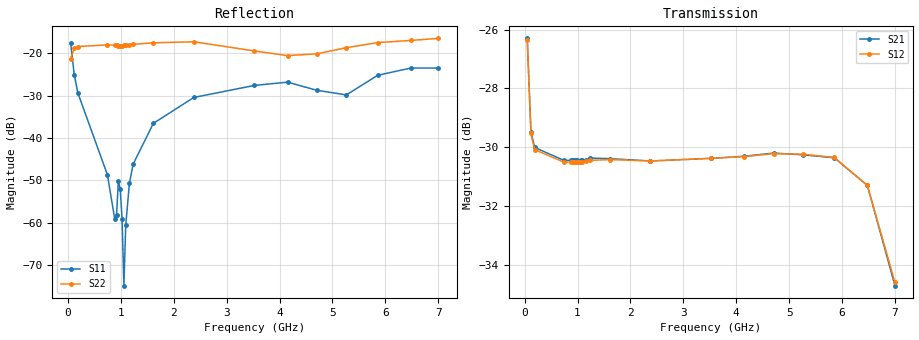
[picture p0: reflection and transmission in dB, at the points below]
! Integrated Device Technology
! Corporate Headquarters
! 6024 Silver Creek Valley Road
! San Jose, CA 95138  USA
! Phone:  1-408-284-8200
! Toll Free:  1-800-223-1366
! Webpage:  http://www.idt.com/
! Timing and RF Division
! 515 Groton Road, Suite 102
! Westford, MA 01886-6024
! Device:  F2258
! Description: Voltage Variable RF Attenuator
! Frequency:  50.0 -  6000.00 MHz
! Package:  3x3 mm Thin QFN Plastic Package: 16 pin
! Ports:  2 RF, 2 DC
!  Pin  1  = NC
!  Pin  2  = NC
!  Pin  3  = RF2  = Port 2
!  Pin  4  = GND
!  Pin  5  = Vdd
!  Pin  6  = NC
!  Pin  7  = VCTRL
!  Pin  8  = NC
!  Pin  9  = GND
!  Pin 10  = RF1  = Port 1
!  Pin 11  = NC
!  Pin 12  = NC
!  Pin 13  = NC
!  Pin 14  = NC
!  Pin 15  = NC
!  Pin 16  = NC
! Vcntrl:  1.680 Volts
! Vdd:  +3.300 Volts
! Current:  1.158 mA
! Data:  The device was measured on a the F2258 evaluation board which has
!  individual transmission lines to the RF pins.  Data was collected
!  using a calibrated network analyzer.  The evaluation board was
!  de-embedded using a TRL calibration technique.
!  The reference plane is the edge of the package pin.
! Misc:  SN 10
!  Action Tracker AT0285
! Date Measured:  2014-12-10
! Date:  2016-01-13  MJV
! Note:
!  Integrated Device Technology supplies this data as a sample of measured
!  data at the package pin for this product.  Your particular data for this
!  product may vary.
!  Data was taken at 25 degrees C.
!  Integrated Device Technology reserves the right to change this data at anytime.
!Freq_(GHz)  S11M_(dB)  S11P_(deg)  S21M_(dB)  S21P_(deg)  S12M_(dB)  S12P_(deg)  S22M_(dB)  S22P_(deg)
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# GHz S dB R 50
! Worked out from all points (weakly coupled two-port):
!   201 points, 50 MHz to 7 GHz, reference 50 ohm
!   highest |S21| = -26.30 dB at 50 MHz (marker M1); lowest = -34.7 dB at 7 GHz (marker M2)
!   lowest |S11| = -74.8 dB at 1.058 GHz (marker M3), VSWR 1.00, Z = 50 + j0.0154 ohm
!   |S11| at or under -10 dB: start of sweep to end of sweep
!   |S22| runs from -21.3 to -16.5 dB; largest |S21 - S12| = 0.00032
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0.05  -17.52 -110.0  -26.30 -51.3  -26.35 -51.4  -21.29 -46.0
0.1195  -25.10 -105.3  -29.47 -27.4  -29.53 -27.4  -18.91 -13.3
0.189  -29.44 -106.9  -30.01 -18.9  -30.08 -19.0  -18.47 -8.8
0.745  -48.62 -127.2  -30.45 -10.6  -30.51 -10.6  -18.08 -9.3
0.884  -59.01 169.5  -30.45 -10.9  -30.50 -10.9  -18.12 -11.1
0.91875  -58.19 135.0  -30.44 -11.0  -30.50 -11.0  -18.12 -11.5
0.9535  -50.07 -148.9  -30.44 -11.1  -30.51 -11.1  -18.33 -10.9
0.98825  -52.11 -161.5  -30.45 -11.2  -30.49 -11.2  -18.31 -11.7
1.023  -58.97 -172.0  -30.46 -11.3  -30.49 -11.3  -18.23 -12.2
1.05775  -74.77 57.3  -30.45 -11.5  -30.50 -11.4  -18.19 -12.3
1.0925  -60.53 48.5  -30.45 -11.6  -30.50 -11.6  -18.18 -12.7
1.162  -50.68 42.7  -30.43 -12.0  -30.47 -11.9  -18.06 -13.5
1.2315  -46.20 31.7  -30.37 -12.4  -30.45 -12.4  -17.95 -14.2
1.61375  -36.56 28.3  -30.39 -15.4  -30.42 -15.3  -17.59 -18.0
2.37825  -30.46 45.6  -30.47 -21.2  -30.47 -21.2  -17.34 -24.5
3.525  -27.62 90.4  -30.38 -30.9  -30.38 -30.9  -19.50 -39.6
4.1505  -26.85 104.4  -30.31 -36.7  -30.32 -36.7  -20.60 -55.2
4.7065  -28.77 94.9  -30.20 -42.2  -30.22 -42.1  -20.18 -64.3
5.2625  -29.85 52.5  -30.26 -48.3  -30.24 -48.4  -18.73 -67.0
5.85325  -25.24 28.7  -30.36 -57.2  -30.35 -57.2  -17.54 -66.8
6.47875  -23.53 40.6  -31.30 -69.7  -31.30 -69.7  -17.03 -82.9
7  -23.52 83.9  -34.71 -70.8  -34.60 -70.8  -16.54 -127.1
